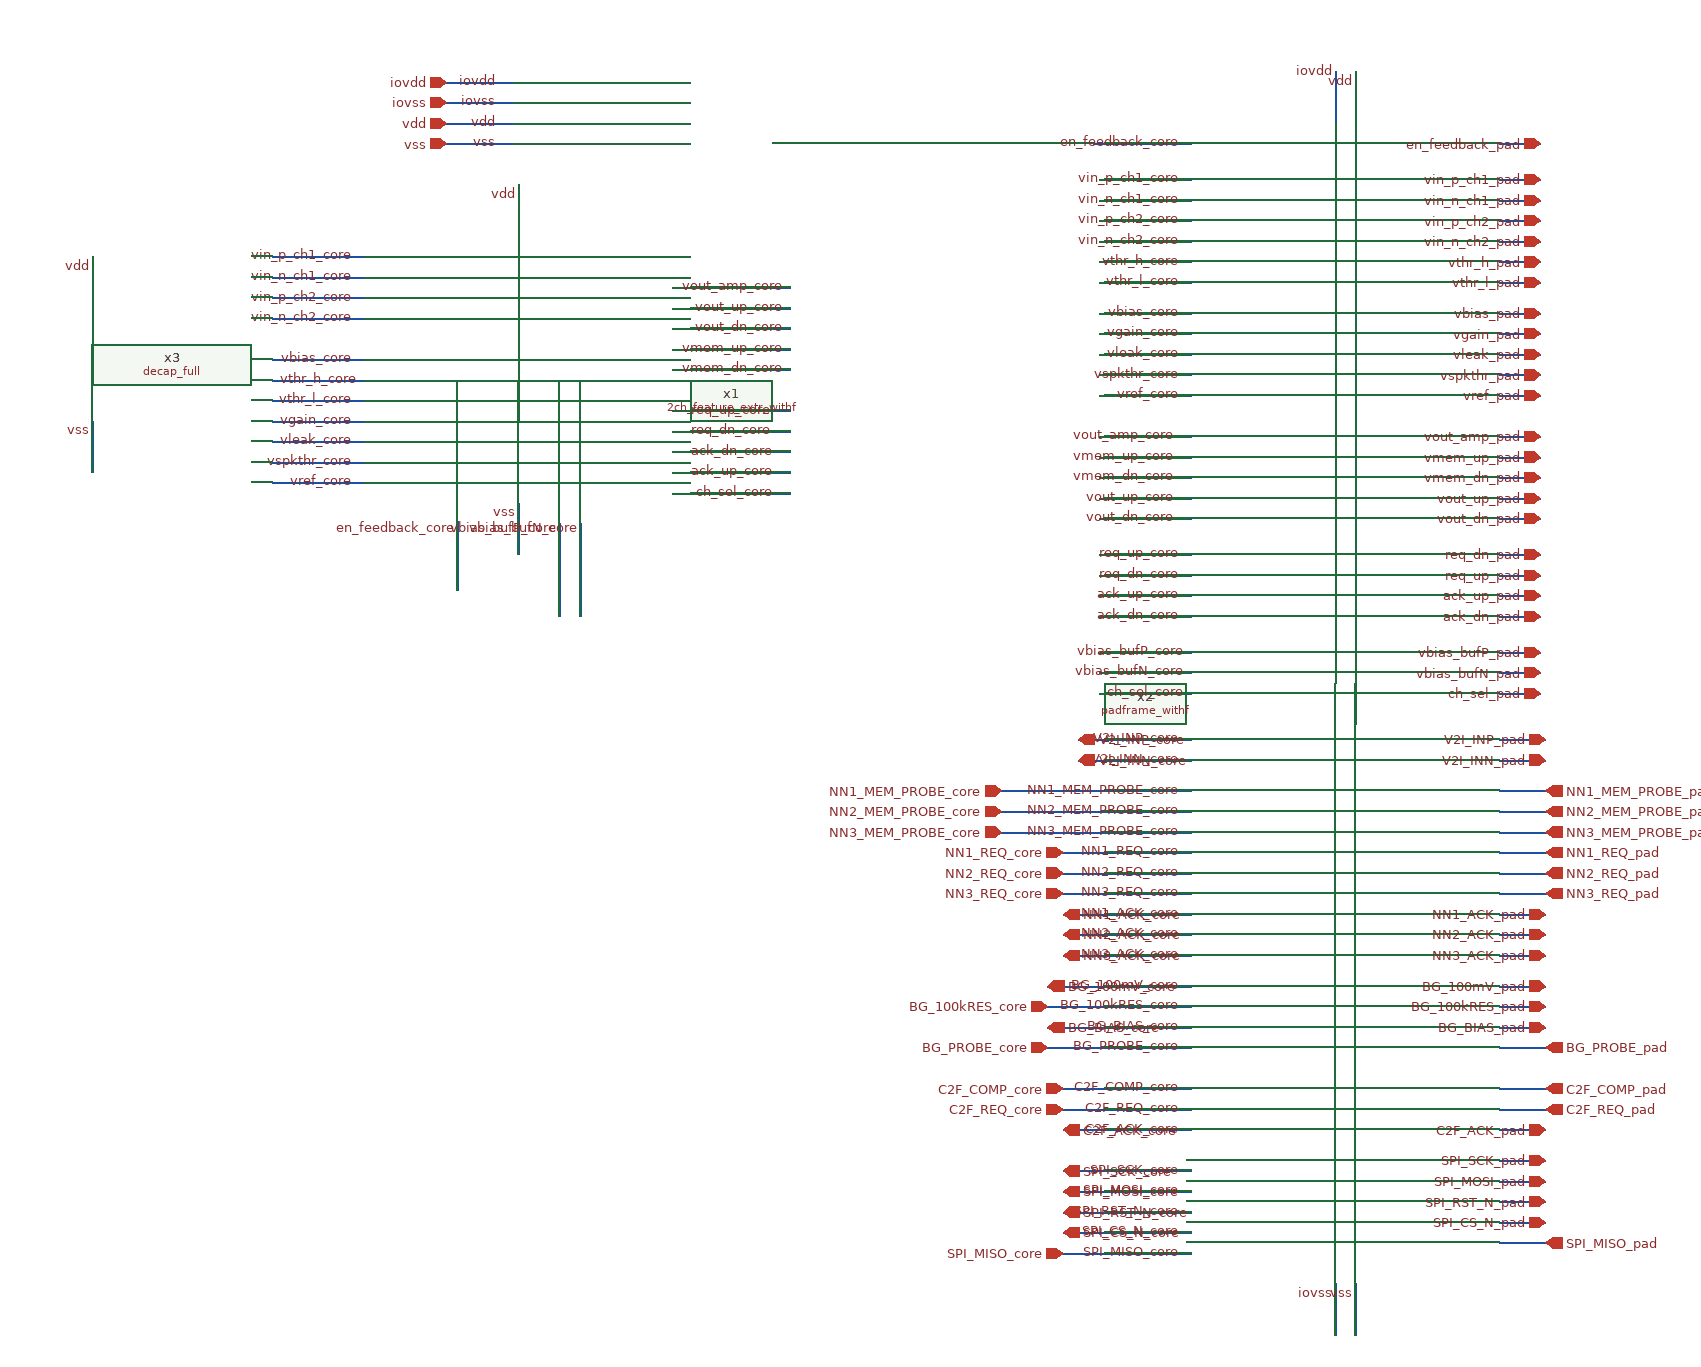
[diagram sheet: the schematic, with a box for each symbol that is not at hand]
v {xschem version=3.4.8RC file_version=1.3}
G {}
K {}
V {}
S {}
F {}
E {}
N -475 -510 -475 -460 {lab=vdd}
N -475 -200 -475 -150 {lab=vss}
N 340 -620 340 -570 {lab=vdd}
N 320 -620 320 -570 {lab=iovdd}
N 320 560 320 610 {lab=iovss}
N 340 560 340 610 {lab=vss}
N -325 -410 -210 -410 {lab=vout_amp_core}
N -325 -390 -210 -390 {lab=vout_up_core}
N -325 -370 -210 -370 {lab=vout_dn_core}
N -325 -350 -210 -350 {lab=vmem_up_core}
N -325 -330 -210 -330 {lab=vmem_dn_core}
N -325 -290 -210 -290 {lab=req_up_core}
N -325 -270 -210 -270 {lab=req_dn_core}
N -325 -250 -210 -250 {lab=ack_dn_core}
N -325 -230 -210 -230 {lab=ack_up_core}
N -325 -210 -210 -210 {lab=ch_sel_core}
N -715 -340 -625 -340 {lab=vbias_core}
N -715 -320 -625 -320 {lab=vthr_h_core}
N -715 -300 -625 -300 {lab=vthr_l_core}
N -715 -280 -625 -280 {lab=vgain_core}
N -715 -260 -625 -260 {lab=vleak_core}
N -715 -240 -625 -240 {lab=vspkthr_core}
N -715 -220 -625 -220 {lab=vref_core}
N 90 -515 180 -515 {lab=vin_p_ch1_core}
N 90 -495 180 -495 {lab=vin_n_ch1_core}
N 90 -475 180 -475 {lab=vin_p_ch2_core}
N 90 -455 180 -455 {lab=vin_n_ch2_core}
N -715 -440 -625 -440 {lab=vin_p_ch1_core}
N -715 -420 -625 -420 {lab=vin_n_ch1_core}
N -715 -400 -625 -400 {lab=vin_p_ch2_core}
N -715 -380 -625 -380 {lab=vin_n_ch2_core}
N 480 -515 520 -515 {lab=vin_p_ch1_pad}
N 480 -495 520 -495 {lab=vin_n_ch1_pad}
N 480 -475 520 -475 {lab=vin_p_ch2_pad}
N 480 -455 520 -455 {lab=vin_n_ch2_pad}
N 480 -435 520 -435 {lab=vthr_h_pad}
N 480 -415 520 -415 {lab=vthr_l_pad}
N 90 -435 180 -435 {lab=vthr_h_core}
N 90 -415 180 -415 {lab=vthr_l_core}
N 480 -385 520 -385 {lab=vbias_pad}
N 480 -365 520 -365 {lab=vgain_pad}
N 480 -345 520 -345 {lab=vleak_pad}
N 480 -325 520 -325 {lab=vspkthr_pad}
N 480 -305 520 -305 {lab=vref_pad}
N 90 -385 180 -385 {lab=vbias_core}
N 90 -365 180 -365 {lab=vgain_core}
N 90 -345 180 -345 {lab=vleak_core}
N 90 -325 180 -325 {lab=vspkthr_core}
N 90 -305 180 -305 {lab=vref_core}
N 480 -265 520 -265 {lab=vout_amp_pad}
N 480 -245 520 -245 {lab=vmem_up_pad}
N 480 -225 520 -225 {lab=vmem_dn_pad}
N 480 -205 520 -205 {lab=vout_up_pad}
N 480 -185 520 -185 {lab=vout_dn_pad}
N 90 -265 180 -265 {lab=vout_amp_core}
N 90 -245 180 -245 {lab=vmem_up_core}
N 90 -225 180 -225 {lab=vmem_dn_core}
N 90 -205 180 -205 {lab=vout_up_core}
N 90 -185 180 -185 {lab=vout_dn_core}
N 90 -150 180 -150 {lab=req_up_core}
N 90 -130 180 -130 {lab=req_dn_core}
N 90 -110 180 -110 {lab=ack_up_core}
N 90 -90 180 -90 {lab=ack_dn_core}
N 480 -150 520 -150 {lab=req_dn_pad}
N 480 -130 520 -130 {lab=req_up_pad}
N 480 -110 520 -110 {lab=ack_up_pad}
N 480 -90 520 -90 {lab=ack_dn_pad}
N 480 -55 520 -55 {lab=vbias_bufP_pad}
N 480 -35 520 -35 {lab=vbias_bufN_pad}
N 90 -55 180 -55 {lab=vbias_bufP_core}
N 90 -35 180 -35 {lab=vbias_bufN_core}
N 90 -15 180 -15 {lab=ch_sel_core}
N -545 -610 -480 -610 {lab=iovdd}
N -545 -590 -480 -590 {lab=iovss}
N -545 -570 -480 -570 {lab=vdd}
N -545 -550 -480 -550 {lab=vss}
N 480 -15 520 -15 {lab=ch_sel_pad}
N -435 -180 -435 -90 {lab=vbias_bufP_core}
N -415 -180 -415 -90 {lab=vbias_bufN_core}
N 70 30 180 30 {lab=V2I_INP_core}
N 70 50 180 50 {lab=V2I_INN_core}
N 480 30 525 30 {lab=V2I_INP_pad}
N 480 50 525 50 {lab=V2I_INN_pad}
N 480 200 525 200 {lab=NN1_ACK_pad}
N 480 220 525 220 {lab=NN2_ACK_pad}
N 480 240 525 240 {lab=NN3_ACK_pad}
N 480 270 525 270 {lab=BG_100mV_pad}
N 480 290 525 290 {lab=BG_100kRES_pad}
N 480 310 525 310 {lab=BG_BIAS_pad}
N 480 410 525 410 {lab=C2F_ACK_pad}
N 480 440 525 440 {lab=SPI_SCK_pad}
N 480 460 525 460 {lab=SPI_MOSI_pad}
N 480 480 525 480 {lab=SPI_RST_N_pad}
N 480 500 525 500 {lab=SPI_CS_N_pad}
N 480 80 525 80 {lab=NN1_MEM_PROBE_pad}
N 480 100 525 100 {lab=NN2_MEM_PROBE_pad}
N 480 120 525 120 {lab=NN3_MEM_PROBE_pad}
N 480 140 525 140 {lab=NN1_REQ_pad}
N 480 160 525 160 {lab=NN2_REQ_pad}
N 480 180 525 180 {lab=NN3_REQ_pad}
N 480 330 525 330 {lab=BG_PROBE_pad}
N 480 370 525 370 {lab=C2F_COMP_pad}
N 480 390 525 390 {lab=C2F_REQ_pad}
N 480 520 525 520 {lab=SPI_MISO_pad}
N -5 80 180 80 {lab=NN1_MEM_PROBE_core}
N -5 100 180 100 {lab=NN2_MEM_PROBE_core}
N -5 120 180 120 {lab=NN3_MEM_PROBE_core}
N 55 200 180 200 {lab=NN1_ACK_core}
N 55 220 180 220 {lab=NN2_ACK_core}
N 55 240 180 240 {lab=NN3_ACK_core}
N 55 180 180 180 {lab=NN3_REQ_core}
N 55 160 180 160 {lab=NN2_REQ_core}
N 55 140 180 140 {lab=NN1_REQ_core}
N 40 270 180 270 {lab=BG_100mV_core}
N 40 290 180 290 {lab=BG_100kRES_core}
N 40 310 180 310 {lab=BG_BIAS_core}
N 40 330 180 330 {lab=BG_PROBE_core}
N 55 410 180 410 {lab=C2F_ACK_core}
N 55 390 180 390 {lab=C2F_REQ_core}
N 55 370 180 370 {lab=C2F_COMP_core}
N 55 450 180 450 {lab=SPI_SCK_core}
N 55 470 180 470 {lab=SPI_MOSI_core}
N 55 490 180 490 {lab=SPI_RST_N_core}
N 55 510 180 510 {lab=SPI_CS_N_core}
N 55 530 180 530 {lab=SPI_MISO_core}
N -535 -182.5 -535 -115 {lab=#net1}
N 480 -550 520 -550 {lab=en_feedback_pad}
N 85 -550 180 -550 {lab=#net2}
N -890 -440 -890 -390 {lab=vdd}
N -890 -280 -890 -230 {lab=vss}
C {2ch_feature_extr_withf.sym} -475 -330 0 0 {name=x1}
C {padframe_withf.sym} 330 10 0 0 {name=x2}
C {lab_wire.sym} -475 -500 3 0 {name=p1 sig_type=std_logic lab=vdd}
C {lab_wire.sym} -475 -190 3 0 {name=p2 sig_type=std_logic lab=vss}
C {lab_wire.sym} 340 -610 3 0 {name=p3 sig_type=std_logic lab=vdd}
C {lab_wire.sym} 320 -620 3 0 {name=p4 sig_type=std_logic lab=iovdd}
C {lab_wire.sym} 320 570 3 0 {name=p5 sig_type=std_logic lab=iovss}
C {lab_wire.sym} 340 570 3 0 {name=p6 sig_type=std_logic lab=vss}
C {lab_wire.sym} 170 -515 0 0 {name=p7 sig_type=std_logic lab=vin_p_ch1_core}
C {lab_wire.sym} 170 -495 0 0 {name=p8 sig_type=std_logic lab=vin_n_ch1_core}
C {lab_wire.sym} 170 -475 0 0 {name=p9 sig_type=std_logic lab=vin_p_ch2_core}
C {lab_wire.sym} 170 -455 0 0 {name=p10 sig_type=std_logic lab=vin_n_ch2_core}
C {lab_wire.sym} -635 -440 0 0 {name=p11 sig_type=std_logic lab=vin_p_ch1_core}
C {lab_wire.sym} -635 -420 0 0 {name=p12 sig_type=std_logic lab=vin_n_ch1_core}
C {lab_wire.sym} -635 -400 0 0 {name=p13 sig_type=std_logic lab=vin_p_ch2_core}
C {lab_wire.sym} -635 -380 0 0 {name=p14 sig_type=std_logic lab=vin_n_ch2_core}
C {ipin.sym} 520 -515 2 0 {name=p_vinpch1_pad lab=vin_p_ch1_pad}
C {ipin.sym} 520 -495 2 0 {name=p_vinnch1_pad lab=vin_n_ch1_pad}
C {ipin.sym} 520 -475 2 0 {name=p_vinpch2_pad lab=vin_p_ch2_pad}
C {ipin.sym} 520 -455 2 0 {name=p_vinnch2_pad lab=vin_n_ch2_pad}
C {ipin.sym} 520 -435 2 0 {name=p_vthrh_pad lab=vthr_h_pad}
C {ipin.sym} 520 -415 2 0 {name=p_vthrl_pad lab=vthr_l_pad}
C {lab_wire.sym} 170 -435 0 0 {name=p15 sig_type=std_logic lab=vthr_h_core}
C {lab_wire.sym} 170 -415 0 0 {name=p16 sig_type=std_logic lab=vthr_l_core}
C {lab_wire.sym} -630 -320 0 0 {name=p17 sig_type=std_logic lab=vthr_h_core}
C {lab_wire.sym} -635 -300 0 0 {name=p18 sig_type=std_logic lab=vthr_l_core}
C {ipin.sym} 520 -385 2 0 {name=p_vbias_pad lab=vbias_pad}
C {ipin.sym} 520 -365 2 0 {name=p_vgain_pad lab=vgain_pad}
C {ipin.sym} 520 -345 2 0 {name=p_vleak_pad lab=vleak_pad}
C {ipin.sym} 520 -325 2 0 {name=p_vspkthr_pad lab=vspkthr_pad}
C {ipin.sym} 520 -305 2 0 {name=p_vref_pad lab=vref_pad}
C {lab_wire.sym} 170 -385 0 0 {name=p19 sig_type=std_logic lab=vbias_core}
C {lab_wire.sym} 170 -365 0 0 {name=p20 sig_type=std_logic lab=vgain_core}
C {lab_wire.sym} 170 -345 0 0 {name=p21 sig_type=std_logic lab=vleak_core}
C {lab_wire.sym} 170 -325 0 0 {name=p22 sig_type=std_logic lab=vspkthr_core}
C {lab_wire.sym} 170 -305 0 0 {name=p23 sig_type=std_logic lab=vref_core}
C {opin.sym} 520 -265 2 1 {name=p_voutamp_pad lab=vout_amp_pad}
C {opin.sym} 520 -245 2 1 {name=p_vmemup_pad lab=vmem_up_pad}
C {opin.sym} 520 -225 2 1 {name=p_vmemdn_pad lab=vmem_dn_pad}
C {opin.sym} 520 -205 2 1 {name=p_voutup_pad lab=vout_up_pad}
C {opin.sym} 520 -185 2 1 {name=p_voutdn_pad lab=vout_dn_pad}
C {lab_wire.sym} 165 -265 0 0 {name=p24 sig_type=std_logic lab=vout_amp_core}
C {lab_wire.sym} 165 -245 0 0 {name=p25 sig_type=std_logic lab=vmem_up_core}
C {lab_wire.sym} 165 -225 0 0 {name=p26 sig_type=std_logic lab=vmem_dn_core}
C {lab_wire.sym} 165 -205 0 0 {name=p27 sig_type=std_logic lab=vout_up_core}
C {lab_wire.sym} 165 -185 0 0 {name=p28 sig_type=std_logic lab=vout_dn_core}
C {lab_wire.sym} -215 -410 0 0 {name=p29 sig_type=std_logic lab=vout_amp_core}
C {lab_wire.sym} -215 -350 0 0 {name=p30 sig_type=std_logic lab=vmem_up_core}
C {lab_wire.sym} -215 -330 0 0 {name=p31 sig_type=std_logic lab=vmem_dn_core}
C {lab_wire.sym} -215 -390 0 0 {name=p32 sig_type=std_logic lab=vout_up_core}
C {lab_wire.sym} -215 -370 0 0 {name=p33 sig_type=std_logic lab=vout_dn_core}
C {lab_wire.sym} 170 -150 0 0 {name=p34 sig_type=std_logic lab=req_up_core}
C {lab_wire.sym} 170 -130 0 0 {name=p35 sig_type=std_logic lab=req_dn_core}
C {lab_wire.sym} 170 -110 0 0 {name=p36 sig_type=std_logic lab=ack_up_core}
C {lab_wire.sym} 170 -90 0 0 {name=p37 sig_type=std_logic lab=ack_dn_core}
C {opin.sym} 520 -150 2 1 {name=p_reqdn_pad lab=req_dn_pad}
C {opin.sym} 520 -130 2 1 {name=p_reqdn_pad1 lab=req_up_pad}
C {ipin.sym} 520 -110 2 0 {name=p_ackup_pad lab=ack_up_pad}
C {ipin.sym} 520 -90 2 0 {name=p_ackdn_pad lab=ack_dn_pad}
C {ipin.sym} 520 -55 2 0 {name=p_vbiasbufP_pad lab=vbias_bufP_pad}
C {ipin.sym} 520 -35 2 0 {name=p_vbiasbufN_pad lab=vbias_bufN_pad}
C {ipin.sym} 520 -15 2 0 {name=p_chsel_pad lab=ch_sel_pad}
C {lab_wire.sym} 175 -55 0 0 {name=p38 sig_type=std_logic lab=vbias_bufP_core}
C {lab_wire.sym} 175 -35 0 0 {name=p39 sig_type=std_logic lab=vbias_bufN_core}
C {lab_wire.sym} 175 -15 0 0 {name=p40 sig_type=std_logic lab=ch_sel_core}
C {lab_wire.sym} -305 -210 0 1 {name=p41 sig_type=std_logic lab=ch_sel_core}
C {lab_wire.sym} -310 -290 0 1 {name=p42 sig_type=std_logic lab=req_up_core}
C {lab_wire.sym} -310 -270 0 1 {name=p43 sig_type=std_logic lab=req_dn_core}
C {lab_wire.sym} -310 -250 0 1 {name=p44 sig_type=std_logic lab=ack_dn_core}
C {lab_wire.sym} -310 -230 0 1 {name=p45 sig_type=std_logic lab=ack_up_core}
C {lab_wire.sym} -635 -340 0 0 {name=p46 sig_type=std_logic lab=vbias_core}
C {lab_wire.sym} -635 -280 0 0 {name=p47 sig_type=std_logic lab=vgain_core}
C {lab_wire.sym} -635 -260 0 0 {name=p48 sig_type=std_logic lab=vleak_core}
C {lab_wire.sym} -635 -240 0 0 {name=p49 sig_type=std_logic lab=vspkthr_core}
C {lab_wire.sym} -635 -220 0 0 {name=p50 sig_type=std_logic lab=vref_core}
C {iopin.sym} -545 -610 2 0 {name=p_iovdd lab=iovdd}
C {iopin.sym} -545 -590 2 0 {name=p_iovss lab=iovss}
C {iopin.sym} -545 -570 2 0 {name=p_vdd lab=vdd}
C {iopin.sym} -545 -550 2 0 {name=p_vss lab=vss}
C {lab_wire.sym} -495 -610 0 0 {name=p51 sig_type=std_logic lab=iovdd}
C {lab_wire.sym} -495 -590 0 0 {name=p52 sig_type=std_logic lab=iovss}
C {lab_wire.sym} -495 -570 0 0 {name=p53 sig_type=std_logic lab=vdd}
C {lab_wire.sym} -495 -550 0 0 {name=p54 sig_type=std_logic lab=vss}
C {lab_wire.sym} -435 -175 3 0 {name=p55 sig_type=std_logic lab=vbias_bufP_core}
C {lab_wire.sym} -415 -175 3 0 {name=p56 sig_type=std_logic lab=vbias_bufN_core}
C {lab_wire.sym} 170 30 0 0 {name=p57 sig_type=std_logic lab=V2I_INP_core}
C {lab_wire.sym} 170 50 0 0 {name=p58 sig_type=std_logic lab=V2I_INN_core}
C {lab_wire.sym} 170 80 0 0 {name=p59 sig_type=std_logic lab=NN1_MEM_PROBE_core}
C {lab_wire.sym} 170 100 0 0 {name=p60 sig_type=std_logic lab=NN2_MEM_PROBE_core}
C {lab_wire.sym} 170 120 0 0 {name=p61 sig_type=std_logic lab=NN3_MEM_PROBE_core}
C {lab_wire.sym} 170 140 0 0 {name=p62 sig_type=std_logic lab=NN1_REQ_core}
C {lab_wire.sym} 170 160 0 0 {name=p63 sig_type=std_logic lab=NN2_REQ_core}
C {lab_wire.sym} 170 180 0 0 {name=p64 sig_type=std_logic lab=NN3_REQ_core}
C {lab_wire.sym} 170 200 0 0 {name=p65 sig_type=std_logic lab=NN1_ACK_core}
C {lab_wire.sym} 170 220 0 0 {name=p66 sig_type=std_logic lab=NN2_ACK_core}
C {lab_wire.sym} 170 240 0 0 {name=p67 sig_type=std_logic lab=NN3_ACK_core}
C {lab_wire.sym} 170 270 0 0 {name=p68 sig_type=std_logic lab=BG_100mV_core}
C {lab_wire.sym} 170 290 0 0 {name=p69 sig_type=std_logic lab=BG_100kRES_core}
C {lab_wire.sym} 170 310 0 0 {name=p70 sig_type=std_logic lab=BG_BIAS_core}
C {lab_wire.sym} 170 330 0 0 {name=p71 sig_type=std_logic lab=BG_PROBE_core}
C {lab_wire.sym} 170 370 0 0 {name=p72 sig_type=std_logic lab=C2F_COMP_core}
C {lab_wire.sym} 170 390 0 0 {name=p73 sig_type=std_logic lab=C2F_REQ_core}
C {lab_wire.sym} 170 410 0 0 {name=p74 sig_type=std_logic lab=C2F_ACK_core}
C {lab_wire.sym} 170 450 0 0 {name=p75 sig_type=std_logic lab=SPI_SCK_core}
C {lab_wire.sym} 170 470 0 0 {name=p76 sig_type=std_logic lab=SPI_MOSI_core}
C {lab_wire.sym} 170 490 0 0 {name=p77 sig_type=std_logic lab=SPI_RST_N_core}
C {lab_wire.sym} 170 510 0 0 {name=p78 sig_type=std_logic lab=SPI_CS_N_core}
C {lab_wire.sym} 170 530 0 0 {name=p79 sig_type=std_logic lab=SPI_MISO_core}
C {ipin.sym} 525 30 2 0 {name=pin_V2I_INP_pad lab=V2I_INP_pad}
C {ipin.sym} 525 50 2 0 {name=pin_V2I_INN_pad lab=V2I_INN_pad}
C {ipin.sym} 525 200 2 0 {name=pin_NN1_ACK_pad lab=NN1_ACK_pad}
C {ipin.sym} 525 220 2 0 {name=pin_NN2_ACK_pad lab=NN2_ACK_pad}
C {ipin.sym} 525 240 2 0 {name=pin_NN3_ACK_pad lab=NN3_ACK_pad}
C {ipin.sym} 525 270 2 0 {name=pin_BG_100mV_pad lab=BG_100mV_pad}
C {iopin.sym} 525 290 0 0 {name=pin_BG_100kRES_pad lab=BG_100kRES_pad}
C {ipin.sym} 525 310 2 0 {name=pin_BG_BIAS_pad lab=BG_BIAS_pad}
C {ipin.sym} 525 410 2 0 {name=pin_C2F_ACK_pad lab=C2F_ACK_pad}
C {ipin.sym} 525 440 2 0 {name=pin_SPI_SCK_pad lab=SPI_SCK_pad}
C {ipin.sym} 525 460 2 0 {name=pin_SPI_MOSI_pad lab=SPI_MOSI_pad}
C {ipin.sym} 525 480 2 0 {name=pin_SPI_RST_N_pad lab=SPI_RST_N_pad}
C {ipin.sym} 525 500 2 0 {name=pin_SPI_CS_N_pad lab=SPI_CS_N_pad}
C {opin.sym} 525 80 0 0 {name=pin_NN1_MEM_PROBE_pad lab=NN1_MEM_PROBE_pad}
C {opin.sym} 525 100 0 0 {name=pin_NN2_MEM_PROBE_pad lab=NN2_MEM_PROBE_pad}
C {opin.sym} 525 120 0 0 {name=pin_NN3_MEM_PROBE_pad lab=NN3_MEM_PROBE_pad}
C {opin.sym} 525 140 0 0 {name=pin_NN1_REQ_pad lab=NN1_REQ_pad}
C {opin.sym} 525 160 0 0 {name=pin_NN2_REQ_pad lab=NN2_REQ_pad}
C {opin.sym} 525 180 0 0 {name=pin_NN3_REQ_pad lab=NN3_REQ_pad}
C {opin.sym} 525 330 0 0 {name=pin_BG_PROBE_pad lab=BG_PROBE_pad}
C {opin.sym} 525 370 0 0 {name=pin_C2F_COMP_pad lab=C2F_COMP_pad}
C {opin.sym} 525 390 0 0 {name=pin_C2F_REQ_pad lab=C2F_REQ_pad}
C {opin.sym} 525 520 0 0 {name=pin_SPI_MISO_pad lab=SPI_MISO_pad}
C {opin.sym} 70 30 2 0 {name=pin_V2I_INP_core lab=V2I_INP_core}
C {opin.sym} 70 50 2 0 {name=pin_V2I_INN_core lab=V2I_INN_core}
C {opin.sym} 55 200 2 0 {name=pin_NN1_ACK_core lab=NN1_ACK_core}
C {opin.sym} 55 220 2 0 {name=pin_NN2_ACK_core lab=NN2_ACK_core}
C {opin.sym} 55 240 2 0 {name=pin_NN3_ACK_core lab=NN3_ACK_core}
C {opin.sym} 40 270 2 0 {name=pin_BG_100mV_core lab=BG_100mV_core}
C {iopin.sym} 40 290 2 0 {name=pin_BG_100kRES_core lab=BG_100kRES_core}
C {opin.sym} 40 310 2 0 {name=pin_BG_BIAS_core lab=BG_BIAS_core}
C {opin.sym} 55 410 2 0 {name=pin_C2F_ACK_core lab=C2F_ACK_core}
C {opin.sym} 55 450 2 0 {name=pin_SPI_SCK_core lab=SPI_SCK_core}
C {opin.sym} 55 470 2 0 {name=pin_SPI_MOSI_core lab=SPI_MOSI_core}
C {opin.sym} 55 490 2 0 {name=pin_SPI_RST_N_core lab=SPI_RST_N_core}
C {opin.sym} 55 510 2 0 {name=pin_SPI_CS_N_core lab=SPI_CS_N_core}
C {ipin.sym} -5 80 0 0 {name=pin_NN1_MEM_PROBE_core lab=NN1_MEM_PROBE_core}
C {ipin.sym} -5 100 0 0 {name=pin_NN2_MEM_PROBE_core lab=NN2_MEM_PROBE_core}
C {ipin.sym} -5 120 0 0 {name=pin_NN3_MEM_PROBE_core lab=NN3_MEM_PROBE_core}
C {ipin.sym} 55 140 0 0 {name=pin_NN1_REQ_core lab=NN1_REQ_core}
C {ipin.sym} 55 160 0 0 {name=pin_NN2_REQ_core lab=NN2_REQ_core}
C {ipin.sym} 55 180 0 0 {name=pin_NN3_REQ_core lab=NN3_REQ_core}
C {ipin.sym} 40 330 0 0 {name=pin_BG_PROBE_core lab=BG_PROBE_core}
C {ipin.sym} 55 370 0 0 {name=pin_C2F_COMP_core lab=C2F_COMP_core}
C {ipin.sym} 55 390 0 0 {name=pin_C2F_REQ_core lab=C2F_REQ_core}
C {ipin.sym} 55 530 0 0 {name=pin_SPI_MISO_core lab=SPI_MISO_core}
C {ipin.sym} 520 -550 2 0 {name=pin_en_feedback_pad lab=en_feedback_pad}
C {lab_wire.sym} 170 -550 0 0 {name=p80 sig_type=std_logic lab=en_feedback_core}
C {lab_wire.sym} -535 -175 3 0 {name=p81 sig_type=std_logic lab=en_feedback_core}
C {decap_full.sym} -890 -340 0 0 {name=x3}
C {lab_wire.sym} -890 -430 3 0 {name=p82 sig_type=std_logic lab=vdd}
C {lab_wire.sym} -890 -270 3 0 {name=p83 sig_type=std_logic lab=vss}
